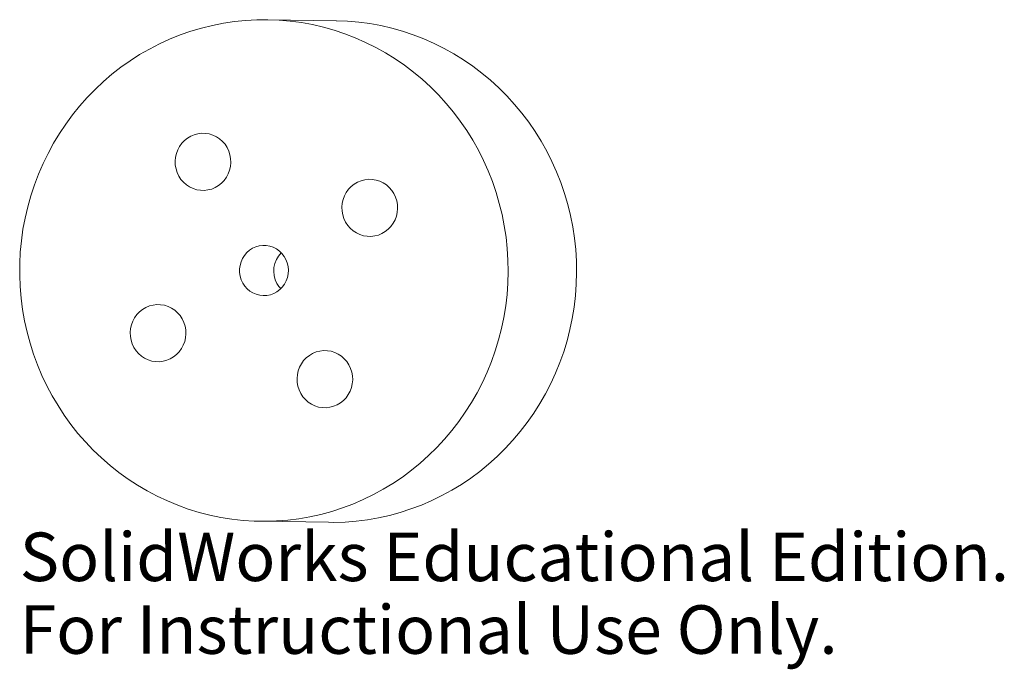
# Model space of a CAD drawing. Units: millimetres. Extents: x -31.2 to 67, y -39.6 to 25.1.
import ezdxf

# ---------------------------------------------------------------- set-up
doc = ezdxf.new("R2010")
doc.units = ezdxf.units.MM
doc.styles.add('SLDTEXTSTYLE0', font='TXT', dxfattribs={"width": 0.7})

msp = doc.modelspace()

# ---------------------------------------------------------------- linework, layer by layer
at = {"color": 7, "linetype": 'Continuous', "lineweight": 15}
for p, q in [((0.37, 24.997), (-6.45, 25.098)), ((-7.19, -24.896), (-0.37, -24.997))]:
    msp.add_line(p, q, dxfattribs=at)
at = {"color": 7, "linetype": 'Continuous', "lineweight": 15, "flags": 128}
for points in [[(-27.92, -12.387), (-27.341, -13.367), (-26.719, -14.318), (-26.055, -15.239), (-25.35, -16.128), (-24.607, -16.983), (-23.826, -17.802), (-23.01, -18.583), (-22.159, -19.325), (-21.276, -20.026), (-20.363, -20.685), (-19.421, -21.3), (-18.453, -21.87), (-17.46, -22.393), (-16.445, -22.87), (-15.41, -23.298), (-14.356, -23.677), (-13.287, -24.006), (-12.204, -24.284), (-11.11, -24.511), (-10.007, -24.686), (-8.897, -24.81), (-7.783, -24.88), (-6.666, -24.898), (-5.55, -24.864), (-4.437, -24.777), (-3.329, -24.638), (-2.228, -24.447), (-1.137, -24.204), (-0.057, -23.91), (1.008, -23.565), (2.057, -23.171), (3.087, -22.728), (4.096, -22.237), (5.082, -21.698), (6.043, -21.114), (6.977, -20.486), (7.882, -19.814), (8.756, -19.1), (9.598, -18.346), (10.405, -17.553), (11.176, -16.723), (11.908, -15.857), (12.602, -14.958), (13.254, -14.027), (13.865, -13.067), (14.432, -12.079), (14.954, -11.065), (15.43, -10.028), (15.86, -8.969), (16.242, -7.892), (16.575, -6.797), (16.859, -5.688), (17.094, -4.567), (17.278, -3.436), (17.411, -2.298), (17.494, -1.155), (17.525, -0.009), (17.505, 1.138), (17.434, 2.282), (17.312, 3.421), (17.14, 4.554), (16.917, 5.677), (16.644, 6.788), (16.321, 7.886), (15.95, 8.967), (15.531, 10.029), (15.065, 11.071), (14.553, 12.089), (13.996, 13.082), (13.396, 14.048), (12.752, 14.985), (12.068, 15.89), (11.344, 16.762), (10.582, 17.599), (9.783, 18.399), (8.949, 19.161), (8.082, 19.882), (7.184, 20.562), (6.256, 21.199), (5.301, 21.792), (4.32, 22.339), (3.316, 22.839), (2.29, 23.292), (1.245, 23.695), (0.184, 24.05), (-0.892, 24.353), (-1.981, 24.606), (-3.08, 24.807), (-4.187, 24.956), (-5.299, 25.053), (-6.415, 25.098), (-7.531, 25.089), (-8.646, 25.029), (-9.758, 24.916), (-10.862, 24.75), (-11.959, 24.533), (-13.044, 24.265), (-14.117, 23.945), (-15.174, 23.576), (-16.214, 23.157), (-17.234, 22.69), (-18.231, 22.175), (-19.205, 21.614), (-20.153, 21.007), (-21.073, 20.357), (-21.963, 19.664), (-22.821, 18.929), (-23.645, 18.156), (-24.434, 17.344), (-25.186, 16.496), (-25.9, 15.613), (-26.573, 14.698), (-27.205, 13.752), (-27.793, 12.778), (-28.338, 11.777), (-28.838, 10.751), (-29.291, 9.703), (-29.697, 8.634), (-30.054, 7.548), (-30.363, 6.446), (-30.623, 5.331), (-30.832, 4.205), (-30.991, 3.07), (-31.099, 1.928), (-31.156, 0.783), (-31.161, -0.363), (-31.116, -1.508), (-31.02, -2.651), (-30.872, -3.787), (-30.674, -4.915), (-30.426, -6.033), (-30.128, -7.137), (-29.781, -8.227), (-29.386, -9.299), (-28.944, -10.351), (-28.455, -11.381), (-27.92, -12.387)], [(-0.37, -24.997), (0.153, -24.999), (1.269, -24.965), (2.383, -24.878), (3.491, -24.739), (4.592, -24.547), (5.683, -24.305), (6.763, -24.011), (7.828, -23.666), (8.876, -23.272), (9.906, -22.829), (10.916, -22.337), (11.902, -21.799), (12.863, -21.215), (13.797, -20.587), (14.702, -19.915), (15.576, -19.201), (16.418, -18.447), (17.225, -17.654), (17.995, -16.823), (18.728, -15.958), (19.422, -15.059), (20.074, -14.128), (20.685, -13.168), (21.252, -12.18), (21.774, -11.166), (22.25, -10.129), (22.68, -9.07), (23.062, -7.993), (23.395, -6.898), (23.679, -5.789), (23.914, -4.668), (24.098, -3.537), (24.231, -2.399), (24.314, -1.255), (24.345, -0.109), (24.325, 1.037), (24.254, 2.181), (24.132, 3.32), (23.96, 4.453), (23.736, 5.576), (23.463, 6.688), (23.141, 7.785), (22.77, 8.866), (22.351, 9.928), (21.885, 10.97), (21.373, 11.988), (20.816, 12.981), (20.215, 13.947), (19.572, 14.884), (18.888, 15.789), (18.164, 16.661), (17.401, 17.498), (16.602, 18.298), (15.769, 19.06), (14.902, 19.782), (14.003, 20.462), (13.076, 21.099), (12.12, 21.691), (11.14, 22.238), (10.135, 22.739), (9.11, 23.191), (8.065, 23.595), (7.004, 23.949), (5.927, 24.252), (4.839, 24.505), (3.74, 24.706), (2.633, 24.855), (1.52, 24.952), (0.405, 24.997), (0.37, 24.997)], [(-15.297, 9.506), (-15.087, 9.183), (-14.835, 8.893), (-14.547, 8.64), (-14.228, 8.43), (-13.884, 8.267), (-13.522, 8.153), (-13.148, 8.092), (-12.769, 8.082), (-12.393, 8.126), (-12.026, 8.223), (-11.675, 8.369), (-11.347, 8.564), (-11.047, 8.802), (-10.782, 9.08), (-10.556, 9.392), (-10.374, 9.734), (-10.238, 10.097), (-10.152, 10.476), (-10.118, 10.863), (-10.134, 11.252), (-10.202, 11.634), (-10.321, 12.004), (-10.487, 12.353), (-10.698, 12.676), (-10.949, 12.967), (-11.237, 13.219), (-11.556, 13.429), (-11.9, 13.592), (-12.262, 13.706), (-12.636, 13.768), (-13.015, 13.777), (-13.391, 13.733), (-13.758, 13.637), (-14.109, 13.49), (-14.437, 13.296), (-14.737, 13.057), (-15.002, 12.779), (-15.228, 12.467), (-15.41, 12.126), (-15.546, 11.762), (-15.632, 11.383), (-15.667, 10.996), (-15.65, 10.607), (-15.582, 10.225), (-15.464, 9.855), (-15.297, 9.506)], [(1.325, 4.921), (1.536, 4.598), (1.788, 4.308), (2.075, 4.055), (2.394, 3.846), (2.738, 3.682), (3.1, 3.569), (3.474, 3.507), (3.853, 3.498), (4.229, 3.542), (4.596, 3.638), (4.947, 3.784), (5.276, 3.979), (5.575, 4.217), (5.84, 4.495), (6.066, 4.808), (6.248, 5.149), (6.384, 5.512), (6.47, 5.891), (6.505, 6.278), (6.488, 6.667), (6.42, 7.05), (6.302, 7.419), (6.136, 7.768), (5.925, 8.091), (5.673, 8.382), (5.385, 8.634), (5.066, 8.844), (4.722, 9.007), (4.36, 9.121), (3.986, 9.183), (3.608, 9.192), (3.231, 9.148), (2.864, 9.052), (2.513, 8.905), (2.185, 8.711), (1.885, 8.472), (1.62, 8.194), (1.394, 7.882), (1.212, 7.541), (1.077, 7.178), (0.991, 6.799), (0.956, 6.411), (0.972, 6.023), (1.04, 5.64), (1.159, 5.271), (1.325, 4.921)], [(-8.93, -1.148), (-8.731, -1.45), (-8.491, -1.719), (-8.215, -1.949), (-7.909, -2.136), (-7.581, -2.274), (-7.236, -2.363), (-6.882, -2.398), (-6.527, -2.381), (-6.179, -2.31), (-5.843, -2.188), (-5.529, -2.018), (-5.242, -1.802), (-4.989, -1.546), (-4.775, -1.254), (-4.604, -0.934), (-4.481, -0.592), (-4.408, -0.234), (-4.385, 0.13), (-4.415, 0.494), (-4.496, 0.849), (-4.627, 1.188), (-4.804, 1.504), (-5.024, 1.791), (-5.283, 2.041), (-5.574, 2.25), (-5.892, 2.413), (-6.23, 2.527), (-6.58, 2.589), (-6.935, 2.598), (-7.288, 2.554), (-7.631, 2.457), (-7.956, 2.311), (-8.258, 2.117), (-8.528, 1.88), (-8.763, 1.606), (-8.956, 1.299), (-9.103, 0.967), (-9.202, 0.616), (-9.25, 0.254), (-9.246, -0.111), (-9.19, -0.471), (-9.084, -0.819), (-8.93, -1.148)], [(-5.52, -1.198), (-5.321, -1.5), (-5.141, -1.709)], [(-19.775, -7.567), (-19.564, -7.89), (-19.313, -8.18), (-19.025, -8.432), (-18.706, -8.642), (-18.362, -8.806), (-18, -8.919), (-17.626, -8.981), (-17.247, -8.99), (-16.871, -8.946), (-16.504, -8.85), (-16.153, -8.703), (-15.824, -8.509), (-15.525, -8.271), (-15.26, -7.993), (-15.034, -7.68), (-14.852, -7.339), (-14.716, -6.976), (-14.63, -6.597), (-14.595, -6.21), (-14.612, -5.821), (-14.68, -5.438), (-14.798, -5.069), (-14.964, -4.719), (-15.175, -4.397), (-15.427, -4.106), (-15.715, -3.854), (-16.034, -3.644), (-16.378, -3.481), (-16.74, -3.367), (-17.114, -3.305), (-17.492, -3.296), (-17.869, -3.34), (-18.236, -3.436), (-18.587, -3.583), (-18.915, -3.777), (-19.215, -4.015), (-19.48, -4.293), (-19.706, -4.606), (-19.888, -4.947), (-20.024, -5.31), (-20.11, -5.689), (-20.144, -6.077), (-20.128, -6.465), (-20.06, -6.848), (-19.941, -7.217), (-19.775, -7.567)], [(1.658, -9.304), (1.824, -9.654), (1.942, -10.023), (2.01, -10.406), (2.027, -10.794), (1.992, -11.182), (1.906, -11.561), (1.771, -11.924), (1.588, -12.265), (1.362, -12.578), (1.097, -12.856), (0.798, -13.094), (0.469, -13.288), (0.119, -13.435), (-0.249, -13.531), (-0.625, -13.575), (-1.004, -13.566), (-1.378, -13.504), (-1.74, -13.39), (-2.083, -13.227), (-2.402, -13.017), (-2.69, -12.765), (-2.942, -12.474), (-3.153, -12.151), (-3.319, -11.802), (-3.437, -11.433), (-3.505, -11.05), (-3.522, -10.661), (-3.487, -10.274), (-3.401, -9.895), (-3.266, -9.532), (-3.083, -9.191), (-2.858, -8.878), (-2.593, -8.6), (-2.293, -8.362), (-1.965, -8.168), (-1.614, -8.021), (-1.247, -7.925), (-0.87, -7.881), (-0.492, -7.89), (-0.118, -7.952), (0.245, -8.065), (0.588, -8.229), (0.907, -8.438), (1.195, -8.691), (1.447, -8.981), (1.658, -9.304)]]:
    msp.add_lwpolyline(points, dxfattribs=at)
at = {"color": 7, "linetype": 'Continuous', "lineweight": 15}
msp.add_arc((-3.3, 0.048), 2.546, 134.63226, 209.30768, dxfattribs=at)

# ---------------------------------------------------------------- texts
at = {"color": 7, "linetype": 'Continuous', "char_height": 4.83362, "attachment_point": 1, "style": 'SLDTEXTSTYLE0'}
for s, insert in [('SolidWorks Educational Edition.', (-31.161, -26.019)), ('For Instructional Use Only.', (-31.161, -33.269))]:
    msp.add_mtext(s, dxfattribs=dict(at, insert=insert))

doc.saveas('drawing.dxf')
